# Generated by FakeRAM 2.0
VERSION 5.7 ;
BUSBITCHARS "[]" ;
PROPERTYDEFINITIONS
  MACRO width INTEGER ;
  MACRO depth INTEGER ;
  MACRO banks INTEGER ;
END PROPERTYDEFINITIONS
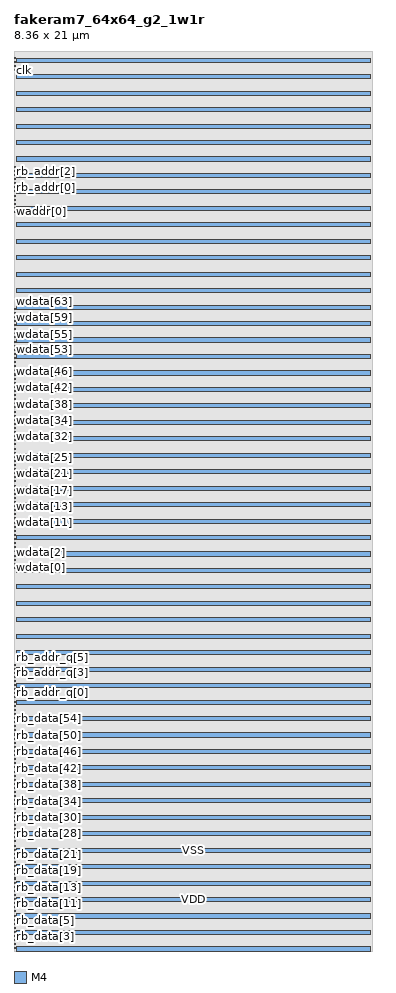
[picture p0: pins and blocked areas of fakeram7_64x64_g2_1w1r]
MACRO fakeram7_64x64_g2_1w1r
  PROPERTY width 64 ;
  PROPERTY depth 64 ;
  PROPERTY banks 1 ;
  FOREIGN fakeram7_64x64_g2_1w1r 0 0 ;
  SYMMETRY X Y R90 ;
  SIZE 8.3600 BY 21.0000 ;
  CLASS BLOCK ;
  PIN wdata[0]
    DIRECTION INPUT ;
    USE SIGNAL ;
    PORT
      LAYER M4 ;
      RECT 0.00000 8.92800 0.02400 8.95200 ;
    END
  END wdata[0]
  PIN wdata[1]
    DIRECTION INPUT ;
    USE SIGNAL ;
    PORT
      LAYER M4 ;
      RECT 0.00000 9.02400 0.02400 9.04800 ;
    END
  END wdata[1]
  PIN wdata[2]
    DIRECTION INPUT ;
    USE SIGNAL ;
    PORT
      LAYER M4 ;
      RECT 0.00000 9.12000 0.02400 9.14400 ;
    END
  END wdata[2]
  PIN wdata[3]
    DIRECTION INPUT ;
    USE SIGNAL ;
    PORT
      LAYER M4 ;
      RECT 0.00000 9.21600 0.02400 9.24000 ;
    END
  END wdata[3]
  PIN wdata[4]
    DIRECTION INPUT ;
    USE SIGNAL ;
    PORT
      LAYER M4 ;
      RECT 0.00000 9.31200 0.02400 9.33600 ;
    END
  END wdata[4]
  PIN wdata[5]
    DIRECTION INPUT ;
    USE SIGNAL ;
    PORT
      LAYER M4 ;
      RECT 0.00000 9.40800 0.02400 9.43200 ;
    END
  END wdata[5]
  PIN wdata[6]
    DIRECTION INPUT ;
    USE SIGNAL ;
    PORT
      LAYER M4 ;
      RECT 0.00000 9.50400 0.02400 9.52800 ;
    END
  END wdata[6]
  PIN wdata[7]
    DIRECTION INPUT ;
    USE SIGNAL ;
    PORT
      LAYER M4 ;
      RECT 0.00000 9.60000 0.02400 9.62400 ;
    END
  END wdata[7]
  PIN wdata[8]
    DIRECTION INPUT ;
    USE SIGNAL ;
    PORT
      LAYER M4 ;
      RECT 0.00000 9.69600 0.02400 9.72000 ;
    END
  END wdata[8]
  PIN wdata[9]
    DIRECTION INPUT ;
    USE SIGNAL ;
    PORT
      LAYER M4 ;
      RECT 0.00000 9.79200 0.02400 9.81600 ;
    END
  END wdata[9]
  PIN wdata[10]
    DIRECTION INPUT ;
    USE SIGNAL ;
    PORT
      LAYER M4 ;
      RECT 0.00000 9.88800 0.02400 9.91200 ;
    END
  END wdata[10]
  PIN wdata[11]
    DIRECTION INPUT ;
    USE SIGNAL ;
    PORT
      LAYER M4 ;
      RECT 0.00000 9.98400 0.02400 10.00800 ;
    END
  END wdata[11]
  PIN wdata[12]
    DIRECTION INPUT ;
    USE SIGNAL ;
    PORT
      LAYER M4 ;
      RECT 0.00000 10.08000 0.02400 10.10400 ;
    END
  END wdata[12]
  PIN wdata[13]
    DIRECTION INPUT ;
    USE SIGNAL ;
    PORT
      LAYER M4 ;
      RECT 0.00000 10.17600 0.02400 10.20000 ;
    END
  END wdata[13]
  PIN wdata[14]
    DIRECTION INPUT ;
    USE SIGNAL ;
    PORT
      LAYER M4 ;
      RECT 0.00000 10.27200 0.02400 10.29600 ;
    END
  END wdata[14]
  PIN wdata[15]
    DIRECTION INPUT ;
    USE SIGNAL ;
    PORT
      LAYER M4 ;
      RECT 0.00000 10.36800 0.02400 10.39200 ;
    END
  END wdata[15]
  PIN wdata[16]
    DIRECTION INPUT ;
    USE SIGNAL ;
    PORT
      LAYER M4 ;
      RECT 0.00000 10.46400 0.02400 10.48800 ;
    END
  END wdata[16]
  PIN wdata[17]
    DIRECTION INPUT ;
    USE SIGNAL ;
    PORT
      LAYER M4 ;
      RECT 0.00000 10.56000 0.02400 10.58400 ;
    END
  END wdata[17]
  PIN wdata[18]
    DIRECTION INPUT ;
    USE SIGNAL ;
    PORT
      LAYER M4 ;
      RECT 0.00000 10.65600 0.02400 10.68000 ;
    END
  END wdata[18]
  PIN wdata[19]
    DIRECTION INPUT ;
    USE SIGNAL ;
    PORT
      LAYER M4 ;
      RECT 0.00000 10.75200 0.02400 10.77600 ;
    END
  END wdata[19]
  PIN wdata[20]
    DIRECTION INPUT ;
    USE SIGNAL ;
    PORT
      LAYER M4 ;
      RECT 0.00000 10.84800 0.02400 10.87200 ;
    END
  END wdata[20]
  PIN wdata[21]
    DIRECTION INPUT ;
    USE SIGNAL ;
    PORT
      LAYER M4 ;
      RECT 0.00000 10.94400 0.02400 10.96800 ;
    END
  END wdata[21]
  PIN wdata[22]
    DIRECTION INPUT ;
    USE SIGNAL ;
    PORT
      LAYER M4 ;
      RECT 0.00000 11.04000 0.02400 11.06400 ;
    END
  END wdata[22]
  PIN wdata[23]
    DIRECTION INPUT ;
    USE SIGNAL ;
    PORT
      LAYER M4 ;
      RECT 0.00000 11.13600 0.02400 11.16000 ;
    END
  END wdata[23]
  PIN wdata[24]
    DIRECTION INPUT ;
    USE SIGNAL ;
    PORT
      LAYER M4 ;
      RECT 0.00000 11.23200 0.02400 11.25600 ;
    END
  END wdata[24]
  PIN wdata[25]
    DIRECTION INPUT ;
    USE SIGNAL ;
    PORT
      LAYER M4 ;
      RECT 0.00000 11.32800 0.02400 11.35200 ;
    END
  END wdata[25]
  PIN wdata[26]
    DIRECTION INPUT ;
    USE SIGNAL ;
    PORT
      LAYER M4 ;
      RECT 0.00000 11.42400 0.02400 11.44800 ;
    END
  END wdata[26]
  PIN wdata[27]
    DIRECTION INPUT ;
    USE SIGNAL ;
    PORT
      LAYER M4 ;
      RECT 0.00000 11.52000 0.02400 11.54400 ;
    END
  END wdata[27]
  PIN wdata[28]
    DIRECTION INPUT ;
    USE SIGNAL ;
    PORT
      LAYER M4 ;
      RECT 0.00000 11.61600 0.02400 11.64000 ;
    END
  END wdata[28]
  PIN wdata[29]
    DIRECTION INPUT ;
    USE SIGNAL ;
    PORT
      LAYER M4 ;
      RECT 0.00000 11.71200 0.02400 11.73600 ;
    END
  END wdata[29]
  PIN wdata[30]
    DIRECTION INPUT ;
    USE SIGNAL ;
    PORT
      LAYER M4 ;
      RECT 0.00000 11.80800 0.02400 11.83200 ;
    END
  END wdata[30]
  PIN wdata[31]
    DIRECTION INPUT ;
    USE SIGNAL ;
    PORT
      LAYER M4 ;
      RECT 0.00000 11.90400 0.02400 11.92800 ;
    END
  END wdata[31]
  PIN wdata[32]
    DIRECTION INPUT ;
    USE SIGNAL ;
    PORT
      LAYER M4 ;
      RECT 0.00000 12.00000 0.02400 12.02400 ;
    END
  END wdata[32]
  PIN wdata[33]
    DIRECTION INPUT ;
    USE SIGNAL ;
    PORT
      LAYER M4 ;
      RECT 0.00000 12.09600 0.02400 12.12000 ;
    END
  END wdata[33]
  PIN wdata[34]
    DIRECTION INPUT ;
    USE SIGNAL ;
    PORT
      LAYER M4 ;
      RECT 0.00000 12.19200 0.02400 12.21600 ;
    END
  END wdata[34]
  PIN wdata[35]
    DIRECTION INPUT ;
    USE SIGNAL ;
    PORT
      LAYER M4 ;
      RECT 0.00000 12.28800 0.02400 12.31200 ;
    END
  END wdata[35]
  PIN wdata[36]
    DIRECTION INPUT ;
    USE SIGNAL ;
    PORT
      LAYER M4 ;
      RECT 0.00000 12.38400 0.02400 12.40800 ;
    END
  END wdata[36]
  PIN wdata[37]
    DIRECTION INPUT ;
    USE SIGNAL ;
    PORT
      LAYER M4 ;
      RECT 0.00000 12.48000 0.02400 12.50400 ;
    END
  END wdata[37]
  PIN wdata[38]
    DIRECTION INPUT ;
    USE SIGNAL ;
    PORT
      LAYER M4 ;
      RECT 0.00000 12.57600 0.02400 12.60000 ;
    END
  END wdata[38]
  PIN wdata[39]
    DIRECTION INPUT ;
    USE SIGNAL ;
    PORT
      LAYER M4 ;
      RECT 0.00000 12.67200 0.02400 12.69600 ;
    END
  END wdata[39]
  PIN wdata[40]
    DIRECTION INPUT ;
    USE SIGNAL ;
    PORT
      LAYER M4 ;
      RECT 0.00000 12.76800 0.02400 12.79200 ;
    END
  END wdata[40]
  PIN wdata[41]
    DIRECTION INPUT ;
    USE SIGNAL ;
    PORT
      LAYER M4 ;
      RECT 0.00000 12.86400 0.02400 12.88800 ;
    END
  END wdata[41]
  PIN wdata[42]
    DIRECTION INPUT ;
    USE SIGNAL ;
    PORT
      LAYER M4 ;
      RECT 0.00000 12.96000 0.02400 12.98400 ;
    END
  END wdata[42]
  PIN wdata[43]
    DIRECTION INPUT ;
    USE SIGNAL ;
    PORT
      LAYER M4 ;
      RECT 0.00000 13.05600 0.02400 13.08000 ;
    END
  END wdata[43]
  PIN wdata[44]
    DIRECTION INPUT ;
    USE SIGNAL ;
    PORT
      LAYER M4 ;
      RECT 0.00000 13.15200 0.02400 13.17600 ;
    END
  END wdata[44]
  PIN wdata[45]
    DIRECTION INPUT ;
    USE SIGNAL ;
    PORT
      LAYER M4 ;
      RECT 0.00000 13.24800 0.02400 13.27200 ;
    END
  END wdata[45]
  PIN wdata[46]
    DIRECTION INPUT ;
    USE SIGNAL ;
    PORT
      LAYER M4 ;
      RECT 0.00000 13.34400 0.02400 13.36800 ;
    END
  END wdata[46]
  PIN wdata[47]
    DIRECTION INPUT ;
    USE SIGNAL ;
    PORT
      LAYER M4 ;
      RECT 0.00000 13.44000 0.02400 13.46400 ;
    END
  END wdata[47]
  PIN wdata[48]
    DIRECTION INPUT ;
    USE SIGNAL ;
    PORT
      LAYER M4 ;
      RECT 0.00000 13.53600 0.02400 13.56000 ;
    END
  END wdata[48]
  PIN wdata[49]
    DIRECTION INPUT ;
    USE SIGNAL ;
    PORT
      LAYER M4 ;
      RECT 0.00000 13.63200 0.02400 13.65600 ;
    END
  END wdata[49]
  PIN wdata[50]
    DIRECTION INPUT ;
    USE SIGNAL ;
    PORT
      LAYER M4 ;
      RECT 0.00000 13.72800 0.02400 13.75200 ;
    END
  END wdata[50]
  PIN wdata[51]
    DIRECTION INPUT ;
    USE SIGNAL ;
    PORT
      LAYER M4 ;
      RECT 0.00000 13.82400 0.02400 13.84800 ;
    END
  END wdata[51]
  PIN wdata[52]
    DIRECTION INPUT ;
    USE SIGNAL ;
    PORT
      LAYER M4 ;
      RECT 0.00000 13.92000 0.02400 13.94400 ;
    END
  END wdata[52]
  PIN wdata[53]
    DIRECTION INPUT ;
    USE SIGNAL ;
    PORT
      LAYER M4 ;
      RECT 0.00000 14.01600 0.02400 14.04000 ;
    END
  END wdata[53]
  PIN wdata[54]
    DIRECTION INPUT ;
    USE SIGNAL ;
    PORT
      LAYER M4 ;
      RECT 0.00000 14.11200 0.02400 14.13600 ;
    END
  END wdata[54]
  PIN wdata[55]
    DIRECTION INPUT ;
    USE SIGNAL ;
    PORT
      LAYER M4 ;
      RECT 0.00000 14.20800 0.02400 14.23200 ;
    END
  END wdata[55]
  PIN wdata[56]
    DIRECTION INPUT ;
    USE SIGNAL ;
    PORT
      LAYER M4 ;
      RECT 0.00000 14.30400 0.02400 14.32800 ;
    END
  END wdata[56]
  PIN wdata[57]
    DIRECTION INPUT ;
    USE SIGNAL ;
    PORT
      LAYER M4 ;
      RECT 0.00000 14.40000 0.02400 14.42400 ;
    END
  END wdata[57]
  PIN wdata[58]
    DIRECTION INPUT ;
    USE SIGNAL ;
    PORT
      LAYER M4 ;
      RECT 0.00000 14.49600 0.02400 14.52000 ;
    END
  END wdata[58]
  PIN wdata[59]
    DIRECTION INPUT ;
    USE SIGNAL ;
    PORT
      LAYER M4 ;
      RECT 0.00000 14.59200 0.02400 14.61600 ;
    END
  END wdata[59]
  PIN wdata[60]
    DIRECTION INPUT ;
    USE SIGNAL ;
    PORT
      LAYER M4 ;
      RECT 0.00000 14.68800 0.02400 14.71200 ;
    END
  END wdata[60]
  PIN wdata[61]
    DIRECTION INPUT ;
    USE SIGNAL ;
    PORT
      LAYER M4 ;
      RECT 0.00000 14.78400 0.02400 14.80800 ;
    END
  END wdata[61]
  PIN wdata[62]
    DIRECTION INPUT ;
    USE SIGNAL ;
    PORT
      LAYER M4 ;
      RECT 0.00000 14.88000 0.02400 14.90400 ;
    END
  END wdata[62]
  PIN wdata[63]
    DIRECTION INPUT ;
    USE SIGNAL ;
    PORT
      LAYER M4 ;
      RECT 0.00000 14.97600 0.02400 15.00000 ;
    END
  END wdata[63]
  PIN waddr[0]
    DIRECTION INPUT ;
    USE SIGNAL ;
    PORT
      LAYER M4 ;
      RECT 0.00000 17.23200 0.02400 17.25600 ;
    END
  END waddr[0]
  PIN waddr[1]
    DIRECTION INPUT ;
    USE SIGNAL ;
    PORT
      LAYER M4 ;
      RECT 0.00000 17.32800 0.02400 17.35200 ;
    END
  END waddr[1]
  PIN waddr[2]
    DIRECTION INPUT ;
    USE SIGNAL ;
    PORT
      LAYER M4 ;
      RECT 0.00000 17.42400 0.02400 17.44800 ;
    END
  END waddr[2]
  PIN waddr[3]
    DIRECTION INPUT ;
    USE SIGNAL ;
    PORT
      LAYER M4 ;
      RECT 0.00000 17.52000 0.02400 17.54400 ;
    END
  END waddr[3]
  PIN waddr[4]
    DIRECTION INPUT ;
    USE SIGNAL ;
    PORT
      LAYER M4 ;
      RECT 0.00000 17.61600 0.02400 17.64000 ;
    END
  END waddr[4]
  PIN waddr[5]
    DIRECTION INPUT ;
    USE SIGNAL ;
    PORT
      LAYER M4 ;
      RECT 0.00000 17.71200 0.02400 17.73600 ;
    END
  END waddr[5]
  PIN rb_data[0]
    DIRECTION OUTPUT ;
    USE SIGNAL ;
    PORT
      LAYER M4 ;
      RECT 0.00000 0.04800 0.02400 0.07200 ;
    END
  END rb_data[0]
  PIN rb_data[1]
    DIRECTION OUTPUT ;
    USE SIGNAL ;
    PORT
      LAYER M4 ;
      RECT 0.00000 0.14400 0.02400 0.16800 ;
    END
  END rb_data[1]
  PIN rb_data[2]
    DIRECTION OUTPUT ;
    USE SIGNAL ;
    PORT
      LAYER M4 ;
      RECT 0.00000 0.24000 0.02400 0.26400 ;
    END
  END rb_data[2]
  PIN rb_data[3]
    DIRECTION OUTPUT ;
    USE SIGNAL ;
    PORT
      LAYER M4 ;
      RECT 0.00000 0.33600 0.02400 0.36000 ;
    END
  END rb_data[3]
  PIN rb_data[4]
    DIRECTION OUTPUT ;
    USE SIGNAL ;
    PORT
      LAYER M4 ;
      RECT 0.00000 0.43200 0.02400 0.45600 ;
    END
  END rb_data[4]
  PIN rb_data[5]
    DIRECTION OUTPUT ;
    USE SIGNAL ;
    PORT
      LAYER M4 ;
      RECT 0.00000 0.52800 0.02400 0.55200 ;
    END
  END rb_data[5]
  PIN rb_data[6]
    DIRECTION OUTPUT ;
    USE SIGNAL ;
    PORT
      LAYER M4 ;
      RECT 0.00000 0.62400 0.02400 0.64800 ;
    END
  END rb_data[6]
  PIN rb_data[7]
    DIRECTION OUTPUT ;
    USE SIGNAL ;
    PORT
      LAYER M4 ;
      RECT 0.00000 0.72000 0.02400 0.74400 ;
    END
  END rb_data[7]
  PIN rb_data[8]
    DIRECTION OUTPUT ;
    USE SIGNAL ;
    PORT
      LAYER M4 ;
      RECT 0.00000 0.81600 0.02400 0.84000 ;
    END
  END rb_data[8]
  PIN rb_data[9]
    DIRECTION OUTPUT ;
    USE SIGNAL ;
    PORT
      LAYER M4 ;
      RECT 0.00000 0.91200 0.02400 0.93600 ;
    END
  END rb_data[9]
  PIN rb_data[10]
    DIRECTION OUTPUT ;
    USE SIGNAL ;
    PORT
      LAYER M4 ;
      RECT 0.00000 1.00800 0.02400 1.03200 ;
    END
  END rb_data[10]
  PIN rb_data[11]
    DIRECTION OUTPUT ;
    USE SIGNAL ;
    PORT
      LAYER M4 ;
      RECT 0.00000 1.10400 0.02400 1.12800 ;
    END
  END rb_data[11]
  PIN rb_data[12]
    DIRECTION OUTPUT ;
    USE SIGNAL ;
    PORT
      LAYER M4 ;
      RECT 0.00000 1.20000 0.02400 1.22400 ;
    END
  END rb_data[12]
  PIN rb_data[13]
    DIRECTION OUTPUT ;
    USE SIGNAL ;
    PORT
      LAYER M4 ;
      RECT 0.00000 1.29600 0.02400 1.32000 ;
    END
  END rb_data[13]
  PIN rb_data[14]
    DIRECTION OUTPUT ;
    USE SIGNAL ;
    PORT
      LAYER M4 ;
      RECT 0.00000 1.39200 0.02400 1.41600 ;
    END
  END rb_data[14]
  PIN rb_data[15]
    DIRECTION OUTPUT ;
    USE SIGNAL ;
    PORT
      LAYER M4 ;
      RECT 0.00000 1.48800 0.02400 1.51200 ;
    END
  END rb_data[15]
  PIN rb_data[16]
    DIRECTION OUTPUT ;
    USE SIGNAL ;
    PORT
      LAYER M4 ;
      RECT 0.00000 1.58400 0.02400 1.60800 ;
    END
  END rb_data[16]
  PIN rb_data[17]
    DIRECTION OUTPUT ;
    USE SIGNAL ;
    PORT
      LAYER M4 ;
      RECT 0.00000 1.68000 0.02400 1.70400 ;
    END
  END rb_data[17]
  PIN rb_data[18]
    DIRECTION OUTPUT ;
    USE SIGNAL ;
    PORT
      LAYER M4 ;
      RECT 0.00000 1.77600 0.02400 1.80000 ;
    END
  END rb_data[18]
  PIN rb_data[19]
    DIRECTION OUTPUT ;
    USE SIGNAL ;
    PORT
      LAYER M4 ;
      RECT 0.00000 1.87200 0.02400 1.89600 ;
    END
  END rb_data[19]
  PIN rb_data[20]
    DIRECTION OUTPUT ;
    USE SIGNAL ;
    PORT
      LAYER M4 ;
      RECT 0.00000 1.96800 0.02400 1.99200 ;
    END
  END rb_data[20]
  PIN rb_data[21]
    DIRECTION OUTPUT ;
    USE SIGNAL ;
    PORT
      LAYER M4 ;
      RECT 0.00000 2.06400 0.02400 2.08800 ;
    END
  END rb_data[21]
  PIN rb_data[22]
    DIRECTION OUTPUT ;
    USE SIGNAL ;
    PORT
      LAYER M4 ;
      RECT 0.00000 2.16000 0.02400 2.18400 ;
    END
  END rb_data[22]
  PIN rb_data[23]
    DIRECTION OUTPUT ;
    USE SIGNAL ;
    PORT
      LAYER M4 ;
      RECT 0.00000 2.25600 0.02400 2.28000 ;
    END
  END rb_data[23]
  PIN rb_data[24]
    DIRECTION OUTPUT ;
    USE SIGNAL ;
    PORT
      LAYER M4 ;
      RECT 0.00000 2.35200 0.02400 2.37600 ;
    END
  END rb_data[24]
  PIN rb_data[25]
    DIRECTION OUTPUT ;
    USE SIGNAL ;
    PORT
      LAYER M4 ;
      RECT 0.00000 2.44800 0.02400 2.47200 ;
    END
  END rb_data[25]
  PIN rb_data[26]
    DIRECTION OUTPUT ;
    USE SIGNAL ;
    PORT
      LAYER M4 ;
      RECT 0.00000 2.54400 0.02400 2.56800 ;
    END
  END rb_data[26]
  PIN rb_data[27]
    DIRECTION OUTPUT ;
    USE SIGNAL ;
    PORT
      LAYER M4 ;
      RECT 0.00000 2.64000 0.02400 2.66400 ;
    END
  END rb_data[27]
  PIN rb_data[28]
    DIRECTION OUTPUT ;
    USE SIGNAL ;
    PORT
      LAYER M4 ;
      RECT 0.00000 2.73600 0.02400 2.76000 ;
    END
  END rb_data[28]
  PIN rb_data[29]
    DIRECTION OUTPUT ;
    USE SIGNAL ;
    PORT
      LAYER M4 ;
      RECT 0.00000 2.83200 0.02400 2.85600 ;
    END
  END rb_data[29]
  PIN rb_data[30]
    DIRECTION OUTPUT ;
    USE SIGNAL ;
    PORT
      LAYER M4 ;
      RECT 0.00000 2.92800 0.02400 2.95200 ;
    END
  END rb_data[30]
  PIN rb_data[31]
    DIRECTION OUTPUT ;
    USE SIGNAL ;
    PORT
      LAYER M4 ;
      RECT 0.00000 3.02400 0.02400 3.04800 ;
    END
  END rb_data[31]
  PIN rb_data[32]
    DIRECTION OUTPUT ;
    USE SIGNAL ;
    PORT
      LAYER M4 ;
      RECT 0.00000 3.12000 0.02400 3.14400 ;
    END
  END rb_data[32]
  PIN rb_data[33]
    DIRECTION OUTPUT ;
    USE SIGNAL ;
    PORT
      LAYER M4 ;
      RECT 0.00000 3.21600 0.02400 3.24000 ;
    END
  END rb_data[33]
  PIN rb_data[34]
    DIRECTION OUTPUT ;
    USE SIGNAL ;
    PORT
      LAYER M4 ;
      RECT 0.00000 3.31200 0.02400 3.33600 ;
    END
  END rb_data[34]
  PIN rb_data[35]
    DIRECTION OUTPUT ;
    USE SIGNAL ;
    PORT
      LAYER M4 ;
      RECT 0.00000 3.40800 0.02400 3.43200 ;
    END
  END rb_data[35]
  PIN rb_data[36]
    DIRECTION OUTPUT ;
    USE SIGNAL ;
    PORT
      LAYER M4 ;
      RECT 0.00000 3.50400 0.02400 3.52800 ;
    END
  END rb_data[36]
  PIN rb_data[37]
    DIRECTION OUTPUT ;
    USE SIGNAL ;
    PORT
      LAYER M4 ;
      RECT 0.00000 3.60000 0.02400 3.62400 ;
    END
  END rb_data[37]
  PIN rb_data[38]
    DIRECTION OUTPUT ;
    USE SIGNAL ;
    PORT
      LAYER M4 ;
      RECT 0.00000 3.69600 0.02400 3.72000 ;
    END
  END rb_data[38]
  PIN rb_data[39]
    DIRECTION OUTPUT ;
    USE SIGNAL ;
    PORT
      LAYER M4 ;
      RECT 0.00000 3.79200 0.02400 3.81600 ;
    END
  END rb_data[39]
  PIN rb_data[40]
    DIRECTION OUTPUT ;
    USE SIGNAL ;
    PORT
      LAYER M4 ;
      RECT 0.00000 3.88800 0.02400 3.91200 ;
    END
  END rb_data[40]
  PIN rb_data[41]
    DIRECTION OUTPUT ;
    USE SIGNAL ;
    PORT
      LAYER M4 ;
      RECT 0.00000 3.98400 0.02400 4.00800 ;
    END
  END rb_data[41]
  PIN rb_data[42]
    DIRECTION OUTPUT ;
    USE SIGNAL ;
    PORT
      LAYER M4 ;
      RECT 0.00000 4.08000 0.02400 4.10400 ;
    END
  END rb_data[42]
  PIN rb_data[43]
    DIRECTION OUTPUT ;
    USE SIGNAL ;
    PORT
      LAYER M4 ;
      RECT 0.00000 4.17600 0.02400 4.20000 ;
    END
  END rb_data[43]
  PIN rb_data[44]
    DIRECTION OUTPUT ;
    USE SIGNAL ;
    PORT
      LAYER M4 ;
      RECT 0.00000 4.27200 0.02400 4.29600 ;
    END
  END rb_data[44]
  PIN rb_data[45]
    DIRECTION OUTPUT ;
    USE SIGNAL ;
    PORT
      LAYER M4 ;
      RECT 0.00000 4.36800 0.02400 4.39200 ;
    END
  END rb_data[45]
  PIN rb_data[46]
    DIRECTION OUTPUT ;
    USE SIGNAL ;
    PORT
      LAYER M4 ;
      RECT 0.00000 4.46400 0.02400 4.48800 ;
    END
  END rb_data[46]
  PIN rb_data[47]
    DIRECTION OUTPUT ;
    USE SIGNAL ;
    PORT
      LAYER M4 ;
      RECT 0.00000 4.56000 0.02400 4.58400 ;
    END
  END rb_data[47]
  PIN rb_data[48]
    DIRECTION OUTPUT ;
    USE SIGNAL ;
    PORT
      LAYER M4 ;
      RECT 0.00000 4.65600 0.02400 4.68000 ;
    END
  END rb_data[48]
  PIN rb_data[49]
    DIRECTION OUTPUT ;
    USE SIGNAL ;
    PORT
      LAYER M4 ;
      RECT 0.00000 4.75200 0.02400 4.77600 ;
    END
  END rb_data[49]
  PIN rb_data[50]
    DIRECTION OUTPUT ;
    USE SIGNAL ;
    PORT
      LAYER M4 ;
      RECT 0.00000 4.84800 0.02400 4.87200 ;
    END
  END rb_data[50]
  PIN rb_data[51]
    DIRECTION OUTPUT ;
    USE SIGNAL ;
    PORT
      LAYER M4 ;
      RECT 0.00000 4.94400 0.02400 4.96800 ;
    END
  END rb_data[51]
  PIN rb_data[52]
    DIRECTION OUTPUT ;
    USE SIGNAL ;
    PORT
      LAYER M4 ;
      RECT 0.00000 5.04000 0.02400 5.06400 ;
    END
  END rb_data[52]
  PIN rb_data[53]
    DIRECTION OUTPUT ;
    USE SIGNAL ;
    PORT
      LAYER M4 ;
      RECT 0.00000 5.13600 0.02400 5.16000 ;
    END
  END rb_data[53]
  PIN rb_data[54]
    DIRECTION OUTPUT ;
    USE SIGNAL ;
    PORT
      LAYER M4 ;
      RECT 0.00000 5.23200 0.02400 5.25600 ;
    END
  END rb_data[54]
  PIN rb_data[55]
    DIRECTION OUTPUT ;
    USE SIGNAL ;
    PORT
      LAYER M4 ;
      RECT 0.00000 5.32800 0.02400 5.35200 ;
    END
  END rb_data[55]
  PIN rb_data[56]
    DIRECTION OUTPUT ;
    USE SIGNAL ;
    PORT
      LAYER M4 ;
      RECT 0.00000 5.42400 0.02400 5.44800 ;
    END
  END rb_data[56]
  PIN rb_data[57]
    DIRECTION OUTPUT ;
    USE SIGNAL ;
    PORT
      LAYER M4 ;
      RECT 0.00000 5.52000 0.02400 5.54400 ;
    END
  END rb_data[57]
  PIN rb_data[58]
    DIRECTION OUTPUT ;
    USE SIGNAL ;
    PORT
      LAYER M4 ;
      RECT 0.00000 5.61600 0.02400 5.64000 ;
    END
  END rb_data[58]
  PIN rb_data[59]
    DIRECTION OUTPUT ;
    USE SIGNAL ;
    PORT
      LAYER M4 ;
      RECT 0.00000 5.71200 0.02400 5.73600 ;
    END
  END rb_data[59]
  PIN rb_data[60]
    DIRECTION OUTPUT ;
    USE SIGNAL ;
    PORT
      LAYER M4 ;
      RECT 0.00000 5.80800 0.02400 5.83200 ;
    END
  END rb_data[60]
  PIN rb_data[61]
    DIRECTION OUTPUT ;
    USE SIGNAL ;
    PORT
      LAYER M4 ;
      RECT 0.00000 5.90400 0.02400 5.92800 ;
    END
  END rb_data[61]
  PIN rb_data[62]
    DIRECTION OUTPUT ;
    USE SIGNAL ;
    PORT
      LAYER M4 ;
      RECT 0.00000 6.00000 0.02400 6.02400 ;
    END
  END rb_data[62]
  PIN rb_data[63]
    DIRECTION OUTPUT ;
    USE SIGNAL ;
    PORT
      LAYER M4 ;
      RECT 0.00000 6.09600 0.02400 6.12000 ;
    END
  END rb_data[63]
  PIN rb_addr[0]
    DIRECTION INPUT ;
    USE SIGNAL ;
    PORT
      LAYER M4 ;
      RECT 0.00000 17.80800 0.02400 17.83200 ;
    END
  END rb_addr[0]
  PIN rb_addr[1]
    DIRECTION INPUT ;
    USE SIGNAL ;
    PORT
      LAYER M4 ;
      RECT 0.00000 17.90400 0.02400 17.92800 ;
    END
  END rb_addr[1]
  PIN rb_addr[2]
    DIRECTION INPUT ;
    USE SIGNAL ;
    PORT
      LAYER M4 ;
      RECT 0.00000 18.00000 0.02400 18.02400 ;
    END
  END rb_addr[2]
  PIN rb_addr[3]
    DIRECTION INPUT ;
    USE SIGNAL ;
    PORT
      LAYER M4 ;
      RECT 0.00000 18.09600 0.02400 18.12000 ;
    END
  END rb_addr[3]
  PIN rb_addr[4]
    DIRECTION INPUT ;
    USE SIGNAL ;
    PORT
      LAYER M4 ;
      RECT 0.00000 18.19200 0.02400 18.21600 ;
    END
  END rb_addr[4]
  PIN rb_addr[5]
    DIRECTION INPUT ;
    USE SIGNAL ;
    PORT
      LAYER M4 ;
      RECT 0.00000 18.28800 0.02400 18.31200 ;
    END
  END rb_addr[5]
  PIN we[0]
    DIRECTION INPUT ;
    USE SIGNAL ;
    PORT
      LAYER M4 ;
      RECT 0.00000 20.64000 0.02400 20.66400 ;
    END
  END we[0]
  PIN we[1]
    DIRECTION INPUT ;
    USE SIGNAL ;
    PORT
      LAYER M4 ;
      RECT 0.00000 20.73600 0.02400 20.76000 ;
    END
  END we[1]
  PIN clk
    DIRECTION INPUT ;
    USE SIGNAL ;
    PORT
      LAYER M4 ;
      RECT 0.00000 20.54400 0.02400 20.56800 ;
    END
  END clk
  PIN rb_en
    DIRECTION INPUT ;
    USE SIGNAL ;
    PORT
      LAYER M4 ;
      RECT 0.00000 20.83200 0.02400 20.85600 ;
    END
  END rb_en
  PIN rb_addr_q[0]
    DIRECTION OUTPUT ;
    USE SIGNAL ;
    PORT
      LAYER M4 ;
      RECT 0.00000 6.19200 0.02400 6.21600 ;
    END
  END rb_addr_q[0]
  PIN rb_addr_q[1]
    DIRECTION OUTPUT ;
    USE SIGNAL ;
    PORT
      LAYER M4 ;
      RECT 0.00000 6.28800 0.02400 6.31200 ;
    END
  END rb_addr_q[1]
  PIN rb_addr_q[2]
    DIRECTION OUTPUT ;
    USE SIGNAL ;
    PORT
      LAYER M4 ;
      RECT 0.00000 6.38400 0.02400 6.40800 ;
    END
  END rb_addr_q[2]
  PIN rb_addr_q[3]
    DIRECTION OUTPUT ;
    USE SIGNAL ;
    PORT
      LAYER M4 ;
      RECT 0.00000 6.48000 0.02400 6.50400 ;
    END
  END rb_addr_q[3]
  PIN rb_addr_q[4]
    DIRECTION OUTPUT ;
    USE SIGNAL ;
    PORT
      LAYER M4 ;
      RECT 0.00000 6.57600 0.02400 6.60000 ;
    END
  END rb_addr_q[4]
  PIN rb_addr_q[5]
    DIRECTION OUTPUT ;
    USE SIGNAL ;
    PORT
      LAYER M4 ;
      RECT 0.00000 6.67200 0.02400 6.69600 ;
    END
  END rb_addr_q[5]
  PIN VDD
    DIRECTION INOUT ;
    USE POWER ;
    PORT
      LAYER M4 ;
      RECT 0.04800 0.38400 8.31200 0.48000 ;
      RECT 0.04800 1.15200 8.31200 1.24800 ;
      RECT 0.04800 1.92000 8.31200 2.01600 ;
      RECT 0.04800 2.68800 8.31200 2.78400 ;
      RECT 0.04800 3.45600 8.31200 3.55200 ;
      RECT 0.04800 4.22400 8.31200 4.32000 ;
      RECT 0.04800 4.99200 8.31200 5.08800 ;
      RECT 0.04800 5.76000 8.31200 5.85600 ;
      RECT 0.04800 6.52800 8.31200 6.62400 ;
      RECT 0.04800 7.29600 8.31200 7.39200 ;
      RECT 0.04800 8.06400 8.31200 8.16000 ;
      RECT 0.04800 8.83200 8.31200 8.92800 ;
      RECT 0.04800 9.60000 8.31200 9.69600 ;
      RECT 0.04800 10.36800 8.31200 10.46400 ;
      RECT 0.04800 11.13600 8.31200 11.23200 ;
      RECT 0.04800 11.90400 8.31200 12.00000 ;
      RECT 0.04800 12.67200 8.31200 12.76800 ;
      RECT 0.04800 13.44000 8.31200 13.53600 ;
      RECT 0.04800 14.20800 8.31200 14.30400 ;
      RECT 0.04800 14.97600 8.31200 15.07200 ;
      RECT 0.04800 15.74400 8.31200 15.84000 ;
      RECT 0.04800 16.51200 8.31200 16.60800 ;
      RECT 0.04800 17.28000 8.31200 17.37600 ;
      RECT 0.04800 18.04800 8.31200 18.14400 ;
      RECT 0.04800 18.81600 8.31200 18.91200 ;
      RECT 0.04800 19.58400 8.31200 19.68000 ;
      RECT 0.04800 20.35200 8.31200 20.44800 ;
    END
  END VDD
  PIN VSS
    DIRECTION INOUT ;
    USE GROUND ;
    PORT
      LAYER M4 ;
      RECT 0.04800 0.00000 8.31200 0.09600 ;
      RECT 0.04800 0.76800 8.31200 0.86400 ;
      RECT 0.04800 1.53600 8.31200 1.63200 ;
      RECT 0.04800 2.30400 8.31200 2.40000 ;
      RECT 0.04800 3.07200 8.31200 3.16800 ;
      RECT 0.04800 3.84000 8.31200 3.93600 ;
      RECT 0.04800 4.60800 8.31200 4.70400 ;
      RECT 0.04800 5.37600 8.31200 5.47200 ;
      RECT 0.04800 6.14400 8.31200 6.24000 ;
      RECT 0.04800 6.91200 8.31200 7.00800 ;
      RECT 0.04800 7.68000 8.31200 7.77600 ;
      RECT 0.04800 8.44800 8.31200 8.54400 ;
      RECT 0.04800 9.21600 8.31200 9.31200 ;
      RECT 0.04800 9.98400 8.31200 10.08000 ;
      RECT 0.04800 10.75200 8.31200 10.84800 ;
      RECT 0.04800 11.52000 8.31200 11.61600 ;
      RECT 0.04800 12.28800 8.31200 12.38400 ;
      RECT 0.04800 13.05600 8.31200 13.15200 ;
      RECT 0.04800 13.82400 8.31200 13.92000 ;
      RECT 0.04800 14.59200 8.31200 14.68800 ;
      RECT 0.04800 15.36000 8.31200 15.45600 ;
      RECT 0.04800 16.12800 8.31200 16.22400 ;
      RECT 0.04800 16.89600 8.31200 16.99200 ;
      RECT 0.04800 17.66400 8.31200 17.76000 ;
      RECT 0.04800 18.43200 8.31200 18.52800 ;
      RECT 0.04800 19.20000 8.31200 19.29600 ;
      RECT 0.04800 19.96800 8.31200 20.06400 ;
      RECT 0.04800 20.73600 8.31200 20.83200 ;
    END
  END VSS
  OBS
    LAYER M1 ;
    RECT 0 0 8.36000 21.00000 ;
    LAYER M2 ;
    RECT 0 0 8.36000 21.00000 ;
    LAYER M3 ;
    RECT 0 0 8.36000 21.00000 ;
    LAYER M4 ;
    RECT 0 0 8.36000 21.00000 ;
  END
END fakeram7_64x64_g2_1w1r

END LIBRARY
